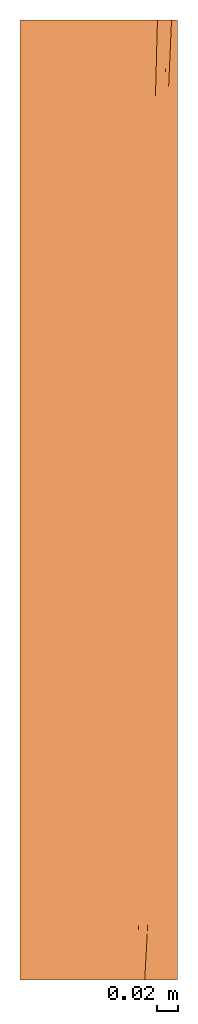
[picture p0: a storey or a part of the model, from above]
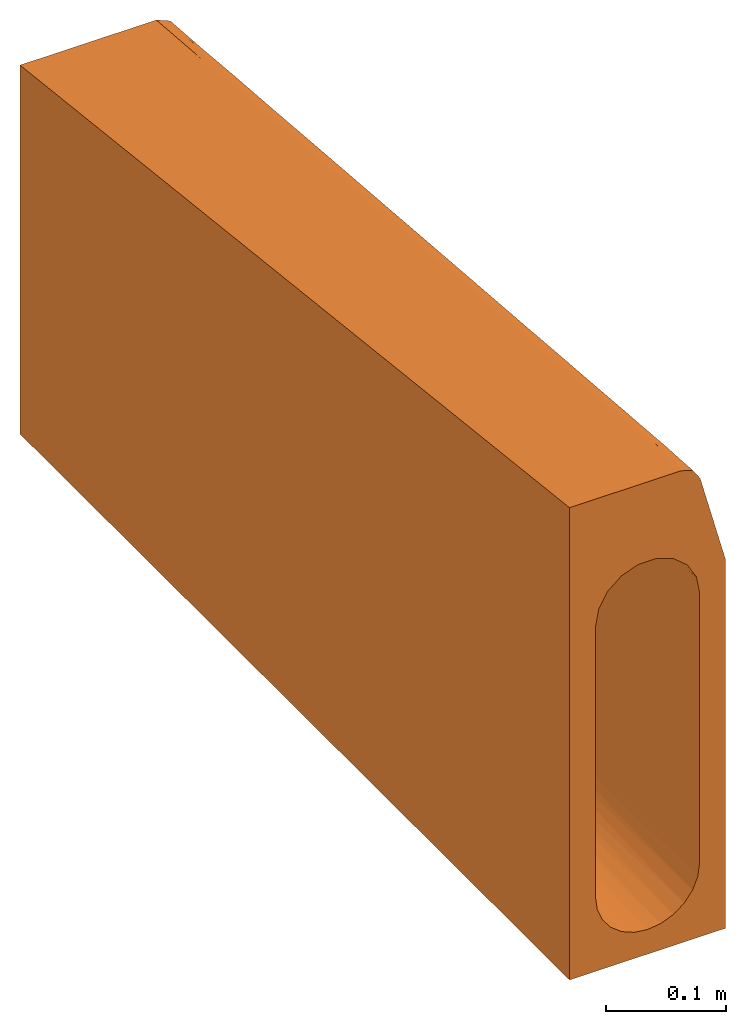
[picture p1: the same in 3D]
Properties of the parts of a building model (IFC2X3)

# File
Description: ViewDefinition [CoordinationView]
File name: 4931 - LH drop kerb - 915mm LG.ifc
Time: 2013-09-18T16:21:28
Written by: Autodesk Revit 2013
Made in: 20120221_2030(x64)

# IfcProject, Project Number
LongName: Project Name; Phase: Project Status

# IfcSite, Default
RefLatitude: 42, 21, 30, 344238; RefLongitude: -71, -3, -35, -194702; RefElevation: 0 mm

# IfcBuilding
Pset_BuildingCommon - NumberOfStoreys: 2
Other - Project Name: Project Name; Project Status: Project Status; Project Issue Date: Issue Date; Project Number: Project Number; Project Address: Enter address here; Client Name: Owner

# IfcBuildingStorey (2)
Constraints - Elevation Base: 0
Graphics - Symbol at End 1 Default: no; Symbol at End 2 Default: yes; Line Pattern: Center; Line Weight: 1; Color: 0; Symbol: M_Level Head - Circle: M_Level Head - Circle
Identity Data - Building Story: yes; Structural: no
Dimensions - Computation Height: 0 mm
Name | LongName = Name | Elevation (mm) = Constraints, Elevation (mm)
T.O. Fnd. Wall | T.O. Fnd. Wall | -300
Level 1 | Level 1 | 0

# IfcBuildingElementProxy: 4931 - LH drop kerb - 915mm LG, Civil-Drainage-Channel-ACO-KerbDrain-HB480(amar):4931 - LH drop kerb - 915mm LG:4931 - LH drop kerb - 915mm LG:481515
In: T.O. Fnd. Wall
Material: ACO Polymer Concrete.
Green Building Properties - End Cap Recyclable: N/A; Channel Recyclable: Fully recyclable; Access Cover/Frame Recyclable: N/A; End Cap Recycled Material Content: N/A; Channel Recycled Material Content: 20% minimum; Access Cover/Frame Recycled Material Content: N/A
Other - Revision: 1; CreatedBy: www.aco.co.uk
Dimensions - Void Start I/O: 0 mm; junction void depth: 2000 mm; Void Length: 915 mm; Junction End: 150 mm; Mitre Long end: 500 mm; Straight Void Start: 0 mm; Void Width: 150 mm; Mitre Small End: 487 mm; Mitre Void End: -4550 mm; Junction Start: 0 mm; Void Depth: -355 mm; Mitre Void Start: -4545 mm; Void End I/O: 150 mm; I/O endcap void depth: 2000 mm; Volume: 30549564 mm3
Phasing - Phase Created: Phase 1
Constraints - Moves With Nearby Elements: no; Level: Level: Level 1
Pset_BuildingElementProxyCommon - Reference: 4931 - LH drop kerb - 915mm LG
Construction - Centre Stone: no; cable loop: no; 7-6m external mitre: no; 25-11m internal mitre: no; LH drop kerb: yes; KDHB480 500_blindunit: no; perforated centre stone: no; RH inlet/outlet end cap: no; Closing end cap: no; HB480-500: no; 10-8m external mitre: no; Junction access unit: no; Access Unit: no; RH drop kerb: no; LH inlet/outlet end cap: no; 25-11m external mitre: no; LH BS transition kerb: no; RH BS transition kerb: no; Bus stop kerb: no; Junction end cap: no; Junction channel: no
Materials and Finishes - End Cap Colour: N/A; Access Cover/Frame Finish: N/A; Channel Material: Vienite® Synthetic Resin Concrete; Channel Colour: Grey; End Cap Material: N/A; Access Cover/Frame Material: N/A; Access Cover/Frame Colour: N/A; Connection Pipe Material: N/A; Connection Pipe Material Colour: N/A
General - TagNumber: 0.000000; SerialNumber: 0.000000
Data - Product Dimensions: 915mm x 150mm x 480/375mm (LxWxH); Drainage Slot Intake area: N/A; Installation - Concrete Grade: Refer to brochure; ACO Hydraulic Design Software: http://www.acodesign.co.uk; Connection Pipe O.D: N/A; Product Standard: BS EN 1433:2002, CE marked, Kitemarked; Load Class: A 15 - D 400; Invert Depth: 455/375mm; Product Weight: 66.7 Kg; Concrete Surround Volume - Load Class A 15 - D 400 - Concrete Pavement: N/A; Hydraulic Performance: http://www.aco.co.uk/download.php?id=120; Drainage Slot Width: N/A; Concrete Surround Volume - Load Class A 15 - D 400 - Grass or Asphalt Pavement: N/A; Channel C.S.A: 0.04 to 0.02mm²
Identity Data - Assembly Code: D2040; OmniClass Number: 23.70.50.24; e-mail Technical: technical@aco.co.uk; Model Description: Combined kerb and drainage system; URL: www.aco.co.uk; Product Page URL: http://www.aco.co.uk/product_detail.php?id=3; Maintenance guidelines: http://www.aco.co.uk/download.php?id=120; Product brochure: http://www.aco.co.uk/download.php?id=120; Manufacturer: ACO Technologies plc - ACO Water Management Division; Telephone: +44 (0)1462 816666; Cost: 0; Type Comments: ACO KerbDrain HB480 half battered left-hand drop kerb unit 915mm long; Address: ACO Business Park, Hitchin Road, Shefford, Bedfordshire, United Kingdom SG17 5TE; Assembly Description: Rain Water Drainage; OmniClass Title: Rainwater Removal; Price: POA - contact ACO; Installation guidelines: http://www.aco.co.uk/download.php?id=120; e-mail Sales: customersupport@aco.co.uk; Product Code: 4931; Model: ACO KerbDrain HB480; Fax: +44 (0)1462 815895

# IfcOpeningElement: Opening (3)
In: Level 1
Structural - Structural: no; Enable Analytical Model: no
Phasing - Phase Created: Phase 1
Dimensions - Thickness: 400 mm; Volume: 2311976250 mm3; Area: 5901750 mm2; Perimeter: 9790 mm
Constraints - Height Offset From Level: 0 mm; Level: Level: Level 1; Related to Mass: no; Room Bounding: yes
Analytical Properties - Thermal mass: 543920; Absorptance: 0.1; Heat Transfer Coefficient (U): 2.0925; Roughness: 1; Thermal Resistance (R): 0.477897
Graphics - Coarse Scale Fill Color: 0
Materials and Finishes - Structural Material: Earth
Construction - Function: 0; Default Thickness: 400 mm

# IfcSlab: Floor:Generic Floor - 400mm, Floor:Generic Floor - 400mm:136426
In: Level 1
PredefinedType: FLOOR; Material: Earth 400 mm
Structural - Structural: no; Enable Analytical Model: no
Phasing - Phase Created: Phase 1
Dimensions - Thickness: 400 mm; Volume: 2311976250 mm3; Area: 5901750 mm2; Perimeter: 9790 mm
Constraints - Height Offset From Level: 0 mm; Level: Level: Level 1; Related to Mass: no; Room Bounding: yes
Pset_SlabCommon - Reference: Generic Floor - 400mm; IsExternal: no; LoadBearing: yes
Analytical Properties - Thermal mass: 543920; Absorptance: 0.1; Heat Transfer Coefficient (U): 2.0925; Roughness: 1; Thermal Resistance (R): 0.477897
Graphics - Coarse Scale Fill Color: 0
Materials and Finishes - Structural Material: Earth
Construction - Function: 0; Default Thickness: 400 mm
